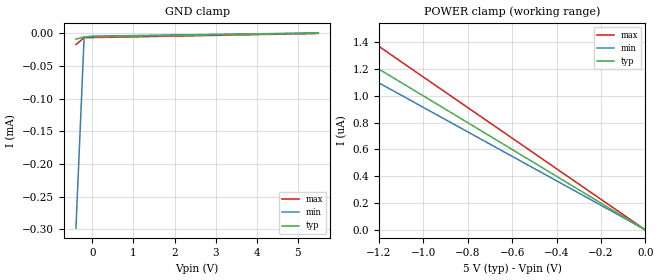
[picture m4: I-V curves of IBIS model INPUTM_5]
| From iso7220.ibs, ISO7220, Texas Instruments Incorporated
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|   INPUTM_5 Model
[Model]   INPUTM_5
Model_type   Input
Vinl = 1.5
Vinh = 3.5
|   typ   min   max
C_comp   1.3pF   1.1pF   1.5pF
[Model Spec]
Vinl   1.50V   1.35V   1.65V
Vinh   3.50V   3.15V   3.85V
|   typ   min   max
[Temperature Range]   27   -40   125
[Voltage range]   5.0V   4.5V   5.5V
[GND_clamp]
|   Voltage   I(typ)   I(min)   I(max)
-400mV    -8.71uA    -298uA     -16.9uA
-200mV    -5.2uA     -5.27uA    -6.5uA
0V        -5uA       -4.1uA     -6.27uA
5.5V      500nA      913nA      27.5pA
[Power_clamp]
| Note that the[POWER_clamp]voltage table is referenced to Vcc
| and is calculated using Vtable=Vcc - Vmeasured.
|   Voltage   I(typ)   I(min)   I(max)
-5.5V     5.498uA    5.021uA    6.28uA
-1.7V     1.699uA    1.552uA    1.939uA
-1.6V     1.599uA    1.461uA    1.825uA
-1.5V     1.499uA    1.369uA    1.711uA
-1.4V     1.399uA    1.278uA    1.597uA
-1.3V     1.299uA    1.187uA    1.483uA
0V        0A         0A         0A
